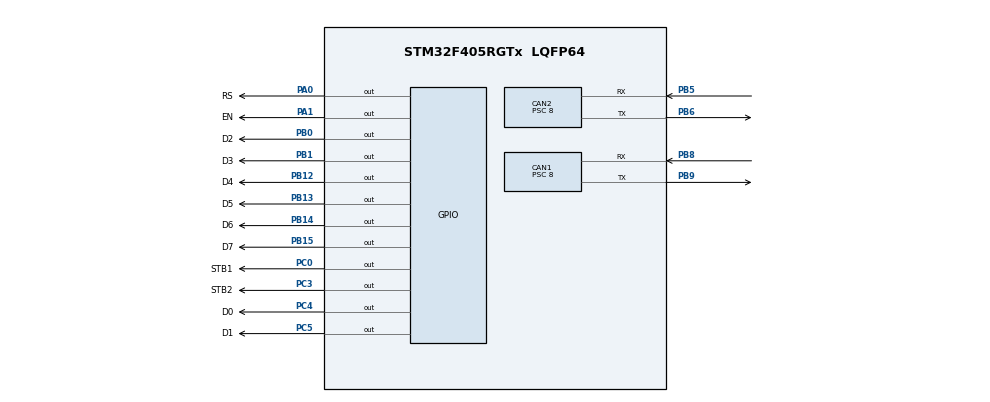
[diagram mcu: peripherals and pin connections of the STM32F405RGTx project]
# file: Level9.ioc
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CAN1.BS1=CAN_BS1_9TQ
CAN1.BS2=CAN_BS2_2TQ
CAN1.CalculateBaudRate=250000
CAN1.CalculateTimeBit=4000
CAN1.CalculateTimeQuantum=333.3333333333333
CAN1.Prescaler=8
CAN2.BS1=CAN_BS1_9TQ
CAN2.BS2=CAN_BS2_2TQ
CAN2.CalculateBaudRate=250000
CAN2.CalculateTimeBit=4000
CAN2.CalculateTimeQuantum=333.3333333333333
CAN2.Prescaler=8
Mcu.Family=STM32F4
Mcu.Name=STM32F405RGTx
Mcu.Package=LQFP64
NVIC.PriorityGroup=NVIC_PRIORITYGROUP_4
PA0-WKUP.GPIO_Label=RS
PA0-WKUP.Signal=GPIO_Output
PA1.GPIO_Label=EN
PA1.Signal=GPIO_Output
PA13.Mode=Serial_Wire
PA13.Signal=SYS_JTMS-SWDIO
PA14.Mode=Serial_Wire
PA14.Signal=SYS_JTCK-SWCLK
PB0.GPIO_Label=D2
PB0.Signal=GPIO_Output
PB1.GPIO_Label=D3
PB1.Signal=GPIO_Output
PB12.GPIO_Label=D4
PB12.Signal=GPIO_Output
PB13.GPIO_Label=D5
PB13.Signal=GPIO_Output
PB14.GPIO_Label=D6
PB14.Signal=GPIO_Output
PB15.GPIO_Label=D7
PB15.Signal=GPIO_Output
PB5.Mode=CAN_Activate
PB5.Signal=CAN2_RX
PB6.Mode=CAN_Activate
PB6.Signal=CAN2_TX
PB8.Mode=CAN_Activate
PB8.Signal=CAN1_RX
PB9.Mode=CAN_Activate
PB9.Signal=CAN1_TX
PC0.GPIO_Label=STB1
PC0.Signal=GPIO_Output
PC14-OSC32_IN.Mode=LSE-External-Oscillator
PC14-OSC32_IN.Signal=RCC_OSC32_IN
PC15-OSC32_OUT.Mode=LSE-External-Oscillator
PC15-OSC32_OUT.Signal=RCC_OSC32_OUT
PC3.GPIO_Label=STB2
PC3.Signal=GPIO_Output
PC4.GPIO_Label=D0
PC4.Signal=GPIO_Output
PC5.GPIO_Label=D1
PC5.Signal=GPIO_Output
PH0-OSC_IN.Mode=HSE-External-Oscillator
PH0-OSC_IN.Signal=RCC_OSC_IN
PH1-OSC_OUT.Mode=HSE-External-Oscillator
PH1-OSC_OUT.Signal=RCC_OSC_OUT
ProjectManager.HeapSize=0x200
ProjectManager.StackSize=0x400
ProjectManager.TargetToolchain=STM32CubeIDE
RCC.48MHZClocksFreq_Value=48000000
RCC.AHBCLKDivider=RCC_SYSCLK_DIV2
RCC.AHBFreq_Value=48000000
RCC.APB1CLKDivider=RCC_HCLK_DIV2
RCC.APB1Freq_Value=24000000
RCC.APB1TimFreq_Value=48000000
RCC.APB2Freq_Value=48000000
RCC.APB2TimFreq_Value=48000000
RCC.CortexFreq_Value=48000000
RCC.HCLKFreq_Value=48000000
RCC.HSE_VALUE=25000000
RCC.HSI_VALUE=16000000
RCC.PLLM=8
RCC.PLLN=96
RCC.SYSCLKFreq_VALUE=96000000
RCC.SYSCLKSource=RCC_SYSCLKSOURCE_PLLCLK
RCC.VCOOutputFreq_Value=192000000
VP_RTC_VS_RTC_Activate.Mode=RTC_Enabled
VP_RTC_VS_RTC_Calendar.Mode=RTC_Calendar
board=custom

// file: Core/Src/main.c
/* USER CODE BEGIN Header */
/**
  ******************************************************************************
  * @file           : main.c
  * @brief          : Main program body
  ******************************************************************************
  * @attention
  *
  * Copyright (c) 2024 STMicroelectronics.
  * All rights reserved.
  *
  * This software is licensed under terms that can be found in the LICENSE file
  * in the root directory of this software component.
  * If no LICENSE file comes with this software, it is provided AS-IS.
  *
  ******************************************************************************
  */
/* USER CODE END Header */
#include "main.h"

CAN_HandleTypeDef hcan1;
CAN_HandleTypeDef hcan2;

RTC_HandleTypeDef hrtc;

/* USER CODE BEGIN PV */
CAN_TxHeaderTypeDef  p1header;
CAN_RxHeaderTypeDef  p2header;
uint32_t pTxMailbox = CAN_TX_MAILBOX0, RxFifo = CAN_RX_FIFO0;
CAN_FilterTypeDef  sFilterConfig;
uint8_t aData[8], received_data[8];
uint8_t can_data, Can_id;

RTC_TimeTypeDef gTime;
RTC_DateTypeDef gDate;
int i;
/* USER CODE END PV */

void SystemClock_Config(void);
static void MX_GPIO_Init(void);
static void MX_CAN1_Init(void);
static void MX_CAN2_Init(void);
static void MX_RTC_Init(void);
/* USER CODE BEGIN PFP */
void lcd_init();
void cmd(unsigned char C);
void data(unsigned char D);
void display(unsigned char *ptr);
void Time(unsigned char Value);
/* USER CODE END PFP */

int main(void)
{

  /* MCU Configuration--------------------------------------------------------*/

  /* Reset of all peripherals, Initializes the Flash interface and the Systick. */
  HAL_Init();

  /* Configure the system clock */
  SystemClock_Config();

  /* Initialize all configured peripherals */
  MX_GPIO_Init();
  MX_CAN1_Init();
  MX_CAN2_Init();
  MX_RTC_Init();

  /* Infinite loop */
  /* USER CODE BEGIN WHILE */
	lcd_init();
	HAL_Delay(500);

	// Set Output pin STB1, STB2 as LOW
	HAL_GPIO_WritePin(GPIOC, STB1_Pin, GPIO_PIN_RESET);
	HAL_GPIO_WritePin(GPIOC, STB2_Pin, GPIO_PIN_RESET);

	// CAN Tx message header configuration
	p1header.DLC = 8;
	p1header.IDE = CAN_ID_STD;
	p1header.StdId = 0x001;
	p1header.RTR = CAN_RTR_DATA;

	// CAN Filter configuration
	sFilterConfig.FilterFIFOAssignment = CAN_FILTER_FIFO0;
	sFilterConfig.FilterIdHigh =0x00C;
	sFilterConfig.FilterIdLow = 0x00A;
	sFilterConfig.FilterMaskIdHigh = 0;
	sFilterConfig.FilterMaskIdLow = 0;
	sFilterConfig.FilterScale = CAN_FILTERSCALE_32BIT;
	sFilterConfig.FilterActivation = ENABLE;
	HAL_CAN_ConfigFilter(&hcan1, &sFilterConfig);
	HAL_CAN_ConfigFilter(&hcan2, &sFilterConfig);

	// Start CAN transmission
	HAL_CAN_Start(&hcan1);
	HAL_CAN_Start(&hcan2);

  while (1)
  {
	HAL_RTC_GetTime(&hrtc,&gTime,RTC_FORMAT_BIN);
	HAL_RTC_GetDate(&hrtc,&gDate,RTC_FORMAT_BIN);

	// Configure data
	aData[0] = gTime.Hours;
	aData[1] = gTime.Minutes;
	aData[2] = gTime.Seconds;
	aData[3] = gDate.WeekDay;
	aData[4] = gDate.Date;
	aData[5] = gDate.Month;
	aData[6] = gDate.Year;
	aData[7] = 00;

	// CAN2 send message and CAN1 receive to perform
	HAL_CAN_AddTxMessage(&hcan2, &p1header, aData, &pTxMailbox);
	HAL_CAN_GetRxMessage(&hcan1, CAN_RX_FIFO0, &p2header, received_data);
	Can_id = p1header.StdId;

	// LCD display base on receive data
	cmd(0x80);
	display("TIME");
	cmd(0x85);
	Time(received_data[0]);
	cmd(0x87);
	display(":");
	cmd(0x88);
	Time(received_data[1]);
	cmd(0x8a);
	display(":");
	cmd(0x8b);
	Time(received_data[2]);

	cmd(0xc0);
	display("DATE");
	cmd(0xc5);
	Time(received_data[4]);
	cmd(0xc7);
	display("/");
	cmd(0xc8);
	Time(received_data[5]);
	cmd(0xca);
	display("/");
	cmd(0xcb);
	Time(received_data[6]);

    /* USER CODE END WHILE */

  }
}

void SystemClock_Config(void)
{
  RCC_OscInitTypeDef RCC_OscInitStruct = {0};
  RCC_ClkInitTypeDef RCC_ClkInitStruct = {0};

  /** Configure the main internal regulator output voltage
  */
  __HAL_RCC_PWR_CLK_ENABLE();
  __HAL_PWR_VOLTAGESCALING_CONFIG(PWR_REGULATOR_VOLTAGE_SCALE1);

  /** Initializes the RCC Oscillators according to the specified parameters
  * in the RCC_OscInitTypeDef structure.
  */
  RCC_OscInitStruct.OscillatorType = RCC_OSCILLATORTYPE_HSI|RCC_OSCILLATORTYPE_LSI;
  RCC_OscInitStruct.HSIState = RCC_HSI_ON;
  RCC_OscInitStruct.HSICalibrationValue = RCC_HSICALIBRATION_DEFAULT;
  RCC_OscInitStruct.LSIState = RCC_LSI_ON;
  RCC_OscInitStruct.PLL.PLLState = RCC_PLL_ON;
  RCC_OscInitStruct.PLL.PLLSource = RCC_PLLSOURCE_HSI;
  RCC_OscInitStruct.PLL.PLLM = 8;
  RCC_OscInitStruct.PLL.PLLN = 72;
  RCC_OscInitStruct.PLL.PLLP = RCC_PLLP_DIV6;
  RCC_OscInitStruct.PLL.PLLQ = 4;
  if (HAL_RCC_OscConfig(&RCC_OscInitStruct) != HAL_OK)
  {
    Error_Handler();
  }

  /** Initializes the CPU, AHB and APB buses clocks
  */
  RCC_ClkInitStruct.ClockType = RCC_CLOCKTYPE_HCLK|RCC_CLOCKTYPE_SYSCLK
                              |RCC_CLOCKTYPE_PCLK1|RCC_CLOCKTYPE_PCLK2;
  RCC_ClkInitStruct.SYSCLKSource = RCC_SYSCLKSOURCE_PLLCLK;
  RCC_ClkInitStruct.AHBCLKDivider = RCC_SYSCLK_DIV1;
  RCC_ClkInitStruct.APB1CLKDivider = RCC_HCLK_DIV1;
  RCC_ClkInitStruct.APB2CLKDivider = RCC_HCLK_DIV1;

  if (HAL_RCC_ClockConfig(&RCC_ClkInitStruct, FLASH_LATENCY_0) != HAL_OK)
  {
    Error_Handler();
  }
}

static void MX_CAN1_Init(void)
{

  hcan1.Instance = CAN1;
  hcan1.Init.Prescaler = 8;
  hcan1.Init.Mode = CAN_MODE_NORMAL;
  hcan1.Init.SyncJumpWidth = CAN_SJW_1TQ;
  hcan1.Init.TimeSeg1 = CAN_BS1_9TQ;
  hcan1.Init.TimeSeg2 = CAN_BS2_2TQ;
  hcan1.Init.TimeTriggeredMode = DISABLE;
  hcan1.Init.AutoBusOff = DISABLE;
  hcan1.Init.AutoWakeUp = DISABLE;
  hcan1.Init.AutoRetransmission = DISABLE;
  hcan1.Init.ReceiveFifoLocked = DISABLE;
  hcan1.Init.TransmitFifoPriority = DISABLE;
  if (HAL_CAN_Init(&hcan1) != HAL_OK)
  {
    Error_Handler();
  }

}

static void MX_CAN2_Init(void)
{

  hcan2.Instance = CAN2;
  hcan2.Init.Prescaler = 8;
  hcan2.Init.Mode = CAN_MODE_NORMAL;
  hcan2.Init.SyncJumpWidth = CAN_SJW_1TQ;
  hcan2.Init.TimeSeg1 = CAN_BS1_9TQ;
  hcan2.Init.TimeSeg2 = CAN_BS2_2TQ;
  hcan2.Init.TimeTriggeredMode = DISABLE;
  hcan2.Init.AutoBusOff = DISABLE;
  hcan2.Init.AutoWakeUp = DISABLE;
  hcan2.Init.AutoRetransmission = DISABLE;
  hcan2.Init.ReceiveFifoLocked = DISABLE;
  hcan2.Init.TransmitFifoPriority = DISABLE;
  if (HAL_CAN_Init(&hcan2) != HAL_OK)
  {
    Error_Handler();
  }

}

static void MX_RTC_Init(void)
{

  RTC_TimeTypeDef sTime = {0};
  RTC_DateTypeDef sDate = {0};
  RTC_TamperTypeDef sTamper = {0};

  /** Initialize RTC Only
  */
  hrtc.Instance = RTC;
  hrtc.Init.HourFormat = RTC_HOURFORMAT_24;
  hrtc.Init.AsynchPrediv = 127;
  hrtc.Init.SynchPrediv = 255;
  hrtc.Init.OutPut = RTC_OUTPUT_DISABLE;
  hrtc.Init.OutPutPolarity = RTC_OUTPUT_POLARITY_HIGH;
  hrtc.Init.OutPutType = RTC_OUTPUT_TYPE_OPENDRAIN;
  if (HAL_RTC_Init(&hrtc) != HAL_OK)
  {
    Error_Handler();
  }

  /** Initialize RTC and set the Time and Date
  */
  sTime.Hours = 0x3;
  sTime.Minutes = 0x26;
  sTime.Seconds = 0x0;
  sTime.DayLightSaving = RTC_DAYLIGHTSAVING_NONE;
  sTime.StoreOperation = RTC_STOREOPERATION_RESET;
  if (HAL_RTC_SetTime(&hrtc, &sTime, RTC_FORMAT_BCD) != HAL_OK)
  {
    Error_Handler();
  }
  sDate.WeekDay = RTC_WEEKDAY_WEDNESDAY;
  sDate.Month = RTC_MONTH_JUNE;
  sDate.Date = 0x10;
  sDate.Year = 0x24;

  if (HAL_RTC_SetDate(&hrtc, &sDate, RTC_FORMAT_BCD) != HAL_OK)
  {
    Error_Handler();
  }

  /** Enable the RTC Tamper 1
  */
  sTamper.Tamper = RTC_TAMPER_1;
  sTamper.PinSelection = RTC_TAMPERPIN_DEFAULT;
  sTamper.Trigger = RTC_TAMPERTRIGGER_RISINGEDGE;
  sTamper.Filter = RTC_TAMPERFILTER_DISABLE;
  sTamper.SamplingFrequency = RTC_TAMPERSAMPLINGFREQ_RTCCLK_DIV32768;
  sTamper.PrechargeDuration = RTC_TAMPERPRECHARGEDURATION_1RTCCLK;
  sTamper.TamperPullUp = RTC_TAMPER_PULLUP_ENABLE;
  sTamper.TimeStampOnTamperDetection = RTC_TIMESTAMPONTAMPERDETECTION_ENABLE;
  if (HAL_RTCEx_SetTamper(&hrtc, &sTamper) != HAL_OK)
  {
    Error_Handler();
  }

}

static void MX_GPIO_Init(void)
{
  GPIO_InitTypeDef GPIO_InitStruct = {0};

  /* GPIO Ports Clock Enable */
  __HAL_RCC_GPIOC_CLK_ENABLE();
  __HAL_RCC_GPIOH_CLK_ENABLE();
  __HAL_RCC_GPIOA_CLK_ENABLE();
  __HAL_RCC_GPIOB_CLK_ENABLE();

  /*Configure GPIO pin Output Level */
  HAL_GPIO_WritePin(GPIOC, STB1_Pin|STB2_Pin|D0_Pin|D1_Pin
                          , GPIO_PIN_RESET);

  /*Configure GPIO pin Output Level */
  HAL_GPIO_WritePin(GPIOA, RS_Pin|EN_Pin, GPIO_PIN_RESET);

  /*Configure GPIO pin Output Level */
  HAL_GPIO_WritePin(GPIOB, D2_Pin|D3_Pin|D4_Pin|D5_Pin
                          |D6_Pin|D7_Pin, GPIO_PIN_RESET);

  /*Configure GPIO pins : STB1_Pin STB2_Pin D0_Pin D1_Pin
                           BUZZ_Pin */
  GPIO_InitStruct.Pin = STB1_Pin|STB2_Pin|D0_Pin|D1_Pin;

  GPIO_InitStruct.Mode = GPIO_MODE_OUTPUT_PP;
  GPIO_InitStruct.Pull = GPIO_NOPULL;
  GPIO_InitStruct.Speed = GPIO_SPEED_FREQ_LOW;
  HAL_GPIO_Init(GPIOC, &GPIO_InitStruct);

  /*Configure GPIO pins : RS_Pin EN_Pin */
  GPIO_InitStruct.Pin = RS_Pin|EN_Pin;
  GPIO_InitStruct.Mode = GPIO_MODE_OUTPUT_PP;
  GPIO_InitStruct.Pull = GPIO_NOPULL;
  GPIO_InitStruct.Speed = GPIO_SPEED_FREQ_LOW;
  HAL_GPIO_Init(GPIOA, &GPIO_InitStruct);

  /*Configure GPIO pins : D2_Pin D3_Pin D4_Pin D5_Pin
                           D6_Pin D7_Pin */
  GPIO_InitStruct.Pin = D2_Pin|D3_Pin|D4_Pin|D5_Pin
                          |D6_Pin|D7_Pin;
  GPIO_InitStruct.Mode = GPIO_MODE_OUTPUT_PP;
  GPIO_InitStruct.Pull = GPIO_NOPULL;
  GPIO_InitStruct.Speed = GPIO_SPEED_FREQ_LOW;
  HAL_GPIO_Init(GPIOB, &GPIO_InitStruct);

}

/* USER CODE BEGIN 4 */
void HAL_RTC_AlarmAEventCallback(RTC_HandleTypeDef *hrtc)
{

}

void lcd_init()
{
	HAL_Delay(10);
	cmd(0x01);
	cmd(0x38);
	cmd(0x06);
	cmd(0x0C);
	HAL_Delay(10);
}

void cmd(unsigned char C)
{
	HAL_GPIO_WritePin(GPIOA, RS_Pin, 0);
	HAL_GPIO_WritePin(GPIOC, D0_Pin,(C&0X01));
	HAL_GPIO_WritePin(GPIOC, D1_Pin,(C&0X02));
	HAL_GPIO_WritePin(GPIOB, D2_Pin,(C&0X04));
	HAL_GPIO_WritePin(GPIOB, D3_Pin,(C&0X08));
	HAL_GPIO_WritePin(GPIOB, D4_Pin,(C&0X10));
	HAL_GPIO_WritePin(GPIOB, D5_Pin,(C&0X20));
	HAL_GPIO_WritePin(GPIOB, D6_Pin,(C&0X40));
	HAL_GPIO_WritePin(GPIOB, D7_Pin,(C&0X80));
	HAL_GPIO_WritePin(GPIOA, EN_Pin, 1);
	HAL_Delay(5);
	HAL_GPIO_WritePin(GPIOA, EN_Pin, 0);
	HAL_Delay(5);
}

void data (unsigned char D)
{
	HAL_GPIO_WritePin(GPIOA, RS_Pin, 1);
	HAL_GPIO_WritePin(GPIOC, D0_Pin,(D&0X01));
	HAL_GPIO_WritePin(GPIOC, D1_Pin,(D&0X02));
	HAL_GPIO_WritePin(GPIOB, D2_Pin,(D&0X04));
	HAL_GPIO_WritePin(GPIOB, D3_Pin,(D&0X08));
	HAL_GPIO_WritePin(GPIOB, D4_Pin,(D&0X10));
	HAL_GPIO_WritePin(GPIOB, D5_Pin,(D&0X20));
	HAL_GPIO_WritePin(GPIOB, D6_Pin,(D&0X40));
	HAL_GPIO_WritePin(GPIOB, D7_Pin,(D&0X80));
	HAL_GPIO_WritePin(GPIOA, EN_Pin, 1);
	HAL_Delay(5);
	HAL_GPIO_WritePin(GPIOA, EN_Pin, 0);
	HAL_Delay(5);
}

void display(unsigned char *ptr)
{
	while(*ptr!='\0')
	{
	data(*ptr++);
	HAL_Delay(2);
	}
}

void Time(unsigned char Value)
{
	data(((Value%100)/10)+0X30);
	data((Value%10)+0X30);
}
/* USER CODE END 4 */

void Error_Handler(void)
{
  __disable_irq();
  while (1)
  {
  }
}
